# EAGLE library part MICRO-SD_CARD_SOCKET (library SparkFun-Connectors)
microSD Socket for Transflash Push-push type µSD socket. tDoc lines correctly indicate media card edge positions when inserting (unlocked, locked, depressed). NOTE: CD1 and CD2 are connected internally, and the default detect state of the socket is detect pin to ground. SparkFun Products: WAV Trigger CAN-Bus Shield SparkFun Level Shifing microSD Breakout

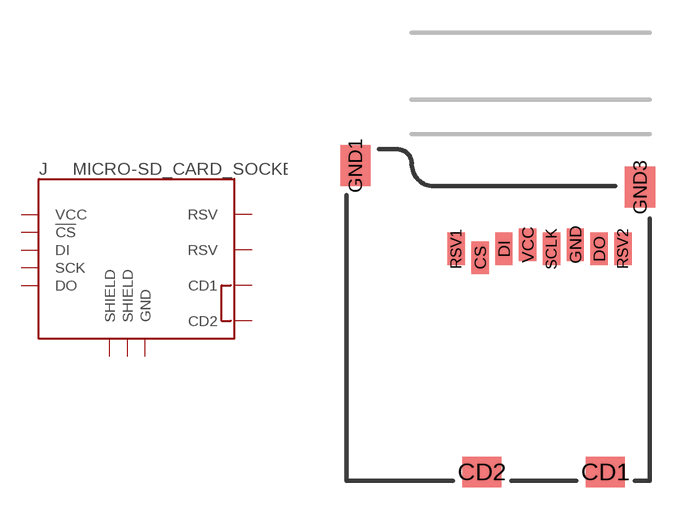
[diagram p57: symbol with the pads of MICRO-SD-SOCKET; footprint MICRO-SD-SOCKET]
Designator prefix J

## MICRO-SD_CARD_SOCKET (PROD_ID: CONN-07820; SF_ID: PRT-00127)  [MICRO-SD-SOCKET]
CD1  CD1
CD2  CD2
CS  !CS
DI  DI
DO  DO
GND  GND
GND1  SHIELD
GND3  SHIELD
RSV1  RSV
RSV2  RSV
SCLK  SCK
VCC  VCC

## Footprint MICRO-SD-SOCKET (pad centres in mm)
microSD Socket SMD Puhs-Push type. tDocu shows location of uSD card in different positions. Specifications: Pin count:12 Datasheet referenced for footprint Example device(s): MICRO-SD_CARD_SOCKET
smd 1.8 x 1.4: CD1 -2.05,0.4; CD2 -7.75,0.4
smd 0.8 x 1.5: CS -7.84,10.3; DI -6.74,10.7; DO -2.34,10.7; GND -3.44,10.9; RSV1 -8.94,10.7; RSV2 -1.24,10.7; SCLK -4.54,10.7; VCC -5.64,10.9
smd 1.4 x 1.9: GND1 -13.6,14.55; GND3 -0.45,13.55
